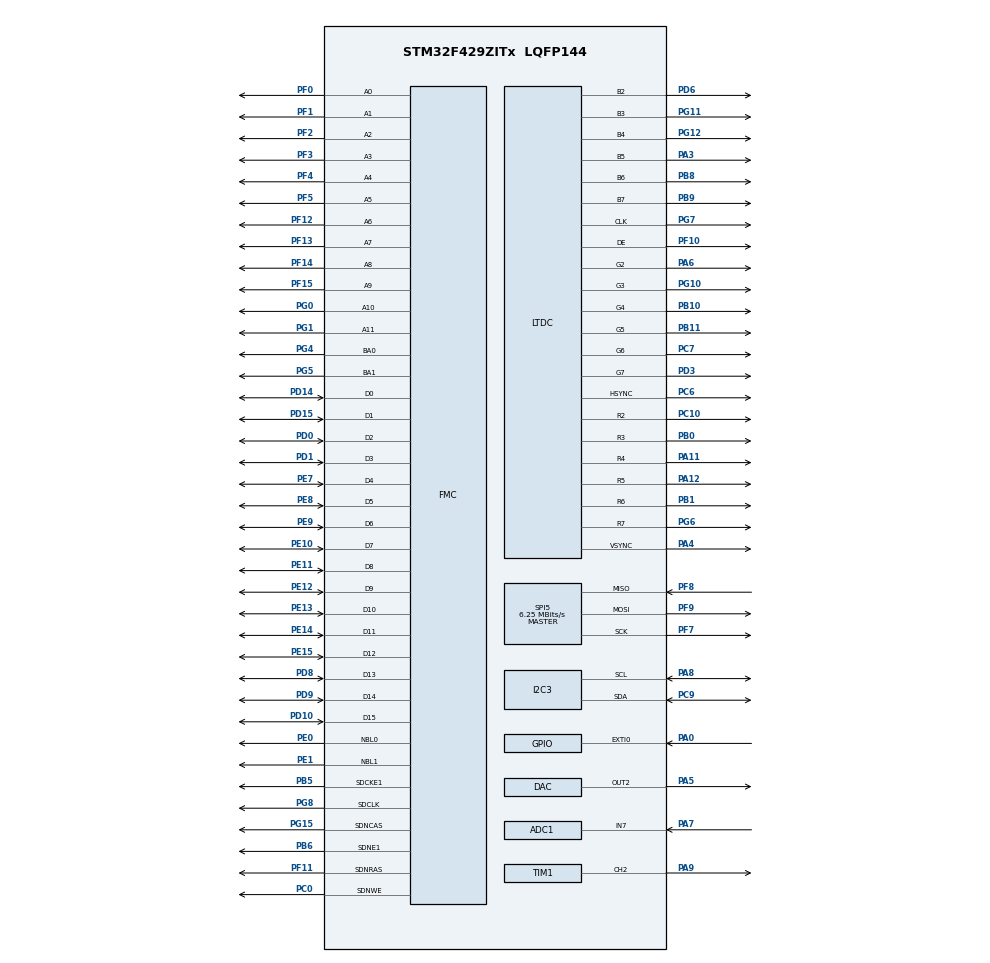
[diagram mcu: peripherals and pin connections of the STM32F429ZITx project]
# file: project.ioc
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ADC1.Channel-0\#ChannelRegularConversion=ADC_CHANNEL_7
ADC1.NbrOfConversionFlag=1
ADC1.Rank-0\#ChannelRegularConversion=1
ADC1.SamplingTime-0\#ChannelRegularConversion=ADC_SAMPLETIME_3CYCLES
ADC1.master=1
DMA2D.ColorMode=DMA2D_OUTPUT_ARGB8888
LTDC.ActiveH=320
LTDC.ActiveW=240
Mcu.Family=STM32F4
Mcu.Name=STM32F429ZITx
Mcu.Package=LQFP144
NVIC.EXTI0_IRQn=true\:0\:0\:false\:false\:true\:true\:true\:true
NVIC.LTDC_IRQn=true\:0\:0\:false\:false\:true\:true\:true\:true
NVIC.PriorityGroup=NVIC_PRIORITYGROUP_4
PA0/WKUP.Signal=GPXTI0
PA11.Mode=RGB666
PA11.Signal=LTDC_R4
PA12.Mode=RGB666
PA12.Signal=LTDC_R5
PA3.Mode=RGB666
PA3.Signal=LTDC_B5
PA4.Mode=RGB666
PA4.Signal=LTDC_VSYNC
PA5.Signal=COMP_DAC2_group
PA6.Mode=RGB666
PA6.Signal=LTDC_G2
PA7.Signal=ADCx_IN7
PA8.Mode=I2C
PA8.Signal=I2C3_SCL
PA9.Signal=S_TIM1_CH2
PB0.Mode=RGB666
PB0.Signal=LTDC_R3
PB1.Mode=RGB666
PB1.Signal=LTDC_R6
PB10.Mode=RGB666
PB10.Signal=LTDC_G4
PB11.Mode=RGB666
PB11.Signal=LTDC_G5
PB5.Mode=SdramChipSelect2_1
PB5.Signal=FMC_SDCKE1
PB6.Mode=SdramChipSelect2_1
PB6.Signal=FMC_SDNE1
PB8.Mode=RGB666
PB8.Signal=LTDC_B6
PB9.Mode=RGB666
PB9.Signal=LTDC_B7
PC0.Signal=FMC_SDNWE
PC10.Mode=RGB666
PC10.Signal=LTDC_R2
PC6.Mode=RGB666
PC6.Signal=LTDC_HSYNC
PC7.Mode=RGB666
PC7.Signal=LTDC_G6
PC9.Mode=I2C
PC9.Signal=I2C3_SDA
PD0.Signal=FMC_D2_DA2
PD1.Signal=FMC_D3_DA3
PD10.Signal=FMC_D15_DA15
PD14.Signal=FMC_D0_DA0
PD15.Signal=FMC_D1_DA1
PD3.Mode=RGB666
PD3.Signal=LTDC_G7
PD6.Mode=RGB666
PD6.Signal=LTDC_B2
PD8.Signal=FMC_D13_DA13
PD9.Signal=FMC_D14_DA14
PE0.Signal=FMC_NBL0
PE1.Signal=FMC_NBL1
PE10.Signal=FMC_D7_DA7
PE11.Signal=FMC_D8_DA8
PE12.Signal=FMC_D9_DA9
PE13.Signal=FMC_D10_DA10
PE14.Signal=FMC_D11_DA11
PE15.Signal=FMC_D12_DA12
PE7.Signal=FMC_D4_DA4
PE8.Signal=FMC_D5_DA5
PE9.Signal=FMC_D6_DA6
PF0.Signal=FMC_A0
PF1.Signal=FMC_A1
PF10.Mode=RGB666
PF10.Signal=LTDC_DE
PF11.Signal=FMC_SDNRAS
PF12.Signal=FMC_A6
PF13.Signal=FMC_A7
PF14.Signal=FMC_A8
PF15.Signal=FMC_A9
PF2.Signal=FMC_A2
PF3.Signal=FMC_A3
PF4.Signal=FMC_A4
PF5.Signal=FMC_A5
PF7.Mode=Full_Duplex_Master
PF7.Signal=SPI5_SCK
PF8.Mode=Full_Duplex_Master
PF8.Signal=SPI5_MISO
PF9.Mode=Full_Duplex_Master
PF9.Signal=SPI5_MOSI
PG0.Signal=FMC_A10
PG1.Signal=FMC_A11
PG10.Mode=RGB666
PG10.Signal=LTDC_G3
PG11.Mode=RGB666
PG11.Signal=LTDC_B3
PG12.Mode=RGB666
PG12.Signal=LTDC_B4
PG15.Signal=FMC_SDNCAS
PG4.Signal=FMC_A14_BA0
PG5.Signal=FMC_A15_BA1
PG6.Mode=RGB666
PG6.Signal=LTDC_R7
PG7.Mode=RGB666
PG7.Signal=LTDC_CLK
PG8.Signal=FMC_SDCLK
PH0/OSC_IN.Mode=HSE-External-Oscillator
PH0/OSC_IN.Signal=RCC_OSC_IN
PH1/OSC_OUT.Mode=HSE-External-Oscillator
PH1/OSC_OUT.Signal=RCC_OSC_OUT
ProjectManager.HeapSize=0x200
ProjectManager.StackSize=0x400
ProjectManager.TargetToolchain=STM32CubeIDE
RCC.48MHZClocksFreq_Value=10000000
RCC.AHBFreq_Value=25000000
RCC.APB1CLKDivider=RCC_HCLK_DIV4
RCC.APB1Freq_Value=6250000
RCC.APB1TimFreq_Value=12500000
RCC.APB2CLKDivider=RCC_HCLK_DIV2
RCC.APB2Freq_Value=12500000
RCC.APB2TimFreq_Value=25000000
RCC.CortexFreq_Value=25000000
RCC.HCLKFreq_Value=25000000
RCC.HSE_VALUE=8000000
RCC.HSI_VALUE=16000000
RCC.LSE_VALUE=32768
RCC.PLLN=100
RCC.PLLQ=5
RCC.PLLSAIR=2
RCC.PLLSourceVirtual=RCC_PLLSOURCE_HSE
RCC.SYSCLKFreq_VALUE=25000000
RCC.SYSCLKSource=RCC_SYSCLKSOURCE_PLLCLK
RCC.VCOOutputFreq_Value=50000000
RTC.Hours=10
RTC.Minutes=15
SH.ADCx_IN7.0=ADC1_IN7,IN7
SH.COMP_DAC2_group.0=DAC_OUT2,DAC_OUT2
SH.FMC_A0.0=FMC_A0,12b-sda1
SH.FMC_A1.0=FMC_A1,12b-sda1
SH.FMC_A10.0=FMC_A10,12b-sda1
SH.FMC_A11.0=FMC_A11,12b-sda1
SH.FMC_A14_BA0.0=FMC_BA0,FourSdramBanks1
SH.FMC_A15_BA1.0=FMC_BA1,FourSdramBanks1
SH.FMC_A2.0=FMC_A2,12b-sda1
SH.FMC_A3.0=FMC_A3,12b-sda1
SH.FMC_A4.0=FMC_A4,12b-sda1
SH.FMC_A5.0=FMC_A5,12b-sda1
SH.FMC_A6.0=FMC_A6,12b-sda1
SH.FMC_A7.0=FMC_A7,12b-sda1
SH.FMC_A8.0=FMC_A8,12b-sda1
SH.FMC_A9.0=FMC_A9,12b-sda1
SH.FMC_D0_DA0.0=FMC_D0,sd-16b-d1
SH.FMC_D10_DA10.0=FMC_D10,sd-16b-d1
SH.FMC_D11_DA11.0=FMC_D11,sd-16b-d1
SH.FMC_D12_DA12.0=FMC_D12,sd-16b-d1
SH.FMC_D13_DA13.0=FMC_D13,sd-16b-d1
SH.FMC_D14_DA14.0=FMC_D14,sd-16b-d1
SH.FMC_D15_DA15.0=FMC_D15,sd-16b-d1
SH.FMC_D1_DA1.0=FMC_D1,sd-16b-d1
SH.FMC_D2_DA2.0=FMC_D2,sd-16b-d1
SH.FMC_D3_DA3.0=FMC_D3,sd-16b-d1
SH.FMC_D4_DA4.0=FMC_D4,sd-16b-d1
SH.FMC_D5_DA5.0=FMC_D5,sd-16b-d1
SH.FMC_D6_DA6.0=FMC_D6,sd-16b-d1
SH.FMC_D7_DA7.0=FMC_D7,sd-16b-d1
SH.FMC_D8_DA8.0=FMC_D8,sd-16b-d1
SH.FMC_D9_DA9.0=FMC_D9,sd-16b-d1
SH.FMC_NBL0.0=FMC_NBL0,Sd2ByteEnable1
SH.FMC_NBL1.0=FMC_NBL1,Sd2ByteEnable1
SH.FMC_SDCLK.0=FMC_SDCLK,12b-sda1
SH.FMC_SDNCAS.0=FMC_SDNCAS,12b-sda1
SH.FMC_SDNRAS.0=FMC_SDNRAS,12b-sda1
SH.FMC_SDNWE.0=FMC_SDNWE,12b-sda1
SH.S_TIM1_CH2.0=TIM1_CH2,PWM Generation2 CH2
SPI5.BaudRatePrescaler=SPI_BAUDRATEPRESCALER_2
SPI5.CalculateBaudRate=6.25 MBits/s
SPI5.Direction=SPI_DIRECTION_2LINES
SPI5.Mode=SPI_MODE_MASTER
SPI5.VirtualType=VM_MASTER
TIM1.Channel-PWM\ Generation2\ CH2=TIM_CHANNEL_2
VP_CRC_VS_CRC.Mode=CRC_Activate
VP_DMA2D_VS_DMA2D.Mode=DMA2D_Activate
VP_RNG_VS_RNG.Mode=RNG_Activate
VP_RTC_VS_RTC_Activate.Mode=RTC_Enabled
VP_RTC_VS_RTC_Calendar.Mode=RTC_Calendar
board=custom

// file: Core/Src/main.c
/* USER CODE BEGIN Header */
/**
 ******************************************************************************
 * @file           : main.c
 * @brief          : Main program body
 ******************************************************************************
 * @attention
 *
 * Copyright (c) 2025 STMicroelectronics.
 * All rights reserved.
 *
 * This software is licensed under terms that can be found in the LICENSE file
 * in the root directory of this software component.
 * If no LICENSE file comes with this software, it is provided AS-IS.
 *
 ******************************************************************************
 */
/* USER CODE END Header */
#include "main.h"

/* USER CODE BEGIN Includes */
#include "stm32f429i_discovery.h"
#include "stm32f429i_discovery_lcd.h"
#include "stm32f429i_discovery_sdram.h"

#include <stdio.h>
#include <stdlib.h>

#include "adc_drv.h"
#include "crc_drv.h"
#include "pwm_drv.h"
#include "rng_utils.h"
#include "rtc_drv.h"
#include "dice.h"
#include "animation.h"
#include "audio.h"
#include "melody.h"
#include "score.h"

/* USER CODE END Includes */

ADC_HandleTypeDef hadc1;

CRC_HandleTypeDef hcrc;

DAC_HandleTypeDef hdac;

DMA2D_HandleTypeDef hdma2d;

I2C_HandleTypeDef hi2c3;

LTDC_HandleTypeDef hltdc;

RNG_HandleTypeDef hrng;

RTC_HandleTypeDef hrtc;

SPI_HandleTypeDef hspi5;

TIM_HandleTypeDef htim1;

SDRAM_HandleTypeDef hsdram1;

/* USER CODE BEGIN PV */
#define ADC_THRESHOLD 5
#define SELECTION_TIMEOUT 5000

extern AudioState_t _audioState;
extern ProtectedScore_t g_HighScoreProtected;
volatile uint8_t g_StartRoll = 0;

typedef enum {
	GAME_START, FIRST_ROLL, SELECTING, REROLL, SCORING
} GameState_t;
GameState_t state = GAME_START;
/* USER CODE END PV */

void SystemClock_Config(void);
static void MX_GPIO_Init(void);
static void MX_RNG_Init(void);
static void MX_DMA2D_Init(void);
static void MX_FMC_Init(void);
static void MX_I2C3_Init(void);
static void MX_LTDC_Init(void);
static void MX_SPI5_Init(void);
static void MX_ADC1_Init(void);
static void MX_CRC_Init(void);
static void MX_DAC_Init(void);
static void MX_RTC_Init(void);
static void MX_TIM1_Init(void);

int main(void) {

	/* MCU Configuration--------------------------------------------------------*/

	/* Reset of all peripherals, Initializes the Flash interface and the Systick. */
	HAL_Init();

	/* Configure the system clock */
	SystemClock_Config();

	/* Initialize all configured peripherals */
	MX_GPIO_Init();
	MX_RNG_Init();
	MX_DMA2D_Init();
	MX_FMC_Init();
	MX_I2C3_Init();
	MX_LTDC_Init();
	MX_SPI5_Init();
	MX_ADC1_Init();
	MX_CRC_Init();
	MX_DAC_Init();
	MX_RTC_Init();
	MX_TIM1_Init();
	/* USER CODE BEGIN 2 */
	// Time initialization
	RTC_SetTime(0, 0, 0);
	RTC_SetDate(0, 0, 0, 0);

	//Video and Audio initialization
	Video_Init();
	Audio_Init(&htim1, TIM_CHANNEL_2);

	// Dice initialization
	const uint16_t count = 5;
	const uint16_t diceSize = 60;

	Dice_t *diceArray[count];
	uint16_t originsX[count];
	uint16_t originsY[count];

	static Dice_t diceObjects[5];
	for (int i = 0; i < count; i++) {
		diceArray[i] = &diceObjects[i];

		if (i == 0 || i == 1) {
			originsY[i] = 70;
			originsX[i] = (i == 0) ? 40 : 140;
		} else if (i == 2) {
			originsY[i] = 135;
			originsX[i] = (240 - diceSize) / 2;
		} else {
			originsY[i] = 200;
			originsX[i] = (i == 3) ? 40 : 140;
		}

		Dice_Init(diceArray[i], originsX[i], originsY[i], diceSize,
		LCD_COLOR_WHITE, LCD_COLOR_RED);
		Dice_SetValue(diceArray[i], RNG_GetValue(1, 6));
	}

	DiceContext_t diceCtx;
	diceCtx.dices = diceArray;
	diceCtx.count = count;
	diceCtx.origX = originsX;
	diceCtx.origY = originsY;

	// Score initialization
	ScoreResult_t res = Dice_CalculateScore(&diceCtx);
	Score_LoadFromBackup();
	if (!IsHighScoreValid()) {
		UpdateHighScore(0, 0);
		Score_SaveToBackup();
	}

	uint32_t highScore = 0;
	uint32_t maxTurns = g_HighScoreProtected.maxTurns;
	uint32_t currentTurns = 0;
	uint32_t currentScore = 0;

	// UI buffors
	char timeBuffer[20];
	char highBuffer[32];
	char turnsBuffer[32];
	char currentBuffer[32];
	char combinationBuffer[32];

	//Reroll mechanism
	uint8_t selectedDiceIndex = 0;
	uint8_t lastPotPercent = 0;
	uint32_t lastActivityTick = 0;
	uint8_t isSelectionActive = 0;

	//Audio test
	//Audio_PlayTone(NOTE_D4, 10);
	uint32_t lastRTCUpdate = 0;

	/* USER CODE END 2 */

	/* Infinite loop */
	/* USER CODE BEGIN WHILE */
	state = GAME_START;
	int8_t lives = 3;
	uint8_t scoringProcessed = 0;

	uint32_t btnPressStart = 0;
	uint8_t btnState = 0;
	const uint32_t LONG_PRESS_MS = 800;

	while (1) {
		/* USER CODE END WHILE */

		/* USER CODE BEGIN 3 */
		uint32_t currentTick = HAL_GetTick();
		uint8_t currentPotPercent = ADC_GetPercentage();
		uint8_t needsRedraw = 0;

		sprintf(highBuffer, "BEST: %lu", highScore);
		sprintf(currentBuffer, "SCORE: %lu", currentScore);
		sprintf(combinationBuffer, "COMBO: %s", res.name);
		sprintf(turnsBuffer, "%lu/%lu", currentTurns, maxTurns);
		RTC_GetTimeStr(timeBuffer);

		if (state
				== SELECTING&& abs((int) currentPotPercent - (int) lastPotPercent) > ADC_THRESHOLD) {
			isSelectionActive = 1;
			lastActivityTick = currentTick;
			lastPotPercent = currentPotPercent;

			selectedDiceIndex =
					(currentPotPercent >= 100) ? 4 : (currentPotPercent / 20);

			needsRedraw = 1;
		}

		if (currentTick - lastRTCUpdate >= 1000) {
			RTC_GetTimeStr(timeBuffer);
			lastRTCUpdate = currentTick;
			needsRedraw = 1;
		}

		if (isSelectionActive
				&& (currentTick - lastActivityTick > SELECTION_TIMEOUT)) {
			isSelectionActive = 0;
			needsRedraw = 1;
		}

		if (_audioState == AUDIO_IDLE && g_StartRoll == 0) {
			Audio_Play(startMelody, sizeof(startMelody) / sizeof(uint32_t));
		}

		switch (state) {
		case GAME_START:
			if (g_StartRoll) {
				g_StartRoll = 0;
				lives = 3;

				state = FIRST_ROLL;
				needsRedraw = 1;
			}
			break;

		case FIRST_ROLL:
			for (int i = 0; i < 5; i++)
				diceArray[i]->isLocked = 0;

			Audio_Play(rollMelody, sizeof(rollMelody) / sizeof(uint32_t));
			Anim_Run(15, &diceCtx, Dice_UpdateLogic, Dice_DrawLogic);
			Dice_RestoreOrigin(&diceCtx);

			res = Dice_CalculateScore(&diceCtx);
			currentScore = res.points;

			lastActivityTick = HAL_GetTick();
			state = SELECTING;
			needsRedraw = 1;
			break;

		case SELECTING:
			int newIndex =
					(currentPotPercent >= 100) ? 4 : (currentPotPercent / 20);
			if (newIndex != selectedDiceIndex) {
				selectedDiceIndex = newIndex;
				lastActivityTick = currentTick;
				needsRedraw = 1;
			}

			g_StartRoll = 0;

			if (HAL_GPIO_ReadPin(GPIOA, GPIO_PIN_0) == GPIO_PIN_SET) {
				if (btnState == 0) {
					btnState = 1;
					btnPressStart = currentTick;
				} else if (btnState == 1) {
					if ((currentTick - btnPressStart) > LONG_PRESS_MS) {
						state = REROLL;
						btnState = 2;
					}
				}
			} else {
				if (btnState == 1) {
					diceArray[selectedDiceIndex]->isLocked =
							!diceArray[selectedDiceIndex]->isLocked;
					needsRedraw = 1;
				}
				btnState = 0;
			}

			break;

		case REROLL:
			Dice_t *rerollArray[5];
			uint16_t rerollOrigX[5];
			uint16_t rerollOrigY[5];
			uint8_t rerollCount = 0;

			for (int i = 0; i < 5; i++) {
				if (!diceArray[i]->isLocked) {
					rerollArray[rerollCount] = diceArray[i];
					rerollOrigX[rerollCount] = originsX[i];
					rerollOrigY[rerollCount] = originsY[i];
					rerollCount++;
				}
			}

			if (rerollCount > 0) {
				DiceContext_t rerollCtx =
						{ .dices = rerollArray, .count = rerollCount, .origX =
								rerollOrigX, .origY = rerollOrigY };

				Audio_Play(rollMelody, sizeof(rollMelody) / sizeof(uint32_t));
				Anim_Run(20, &rerollCtx, Dice_UpdateLogic, Dice_DrawLogic);
				Dice_RestoreOrigin(&rerollCtx);
			}
			state = SCORING;
			scoringProcessed = 0;
			needsRedraw = 1;
			break;

		case SCORING:
			if (!scoringProcessed) {
				res = Dice_CalculateScore(&diceCtx);
				needsRedraw = 1;
				scoringProcessed = 1;

				currentTurns++;
				if (currentTurns > maxTurns) {
					maxTurns = currentTurns;
				}

				if (currentScore > highScore) {
					highScore = currentScore;
					UpdateHighScore(highScore, maxTurns);
					Score_SaveToBackup();

					Audio_Play(winMelody, sizeof(winMelody) / sizeof(uint32_t));
				} else {
					lives--;
					if (lives <= 0) {
						Audio_Play(gameOverMelody,
								sizeof(gameOverMelody) / sizeof(uint32_t));

						highScore = 0;
						currentTurns = 0;
						UpdateHighScore(0, maxTurns);
						Score_SaveToBackup();
					} else {
						Audio_Play(loseLifeMelody,
								sizeof(loseLifeMelody) / sizeof(uint32_t));
					}
					needsRedraw = 1;
				}

				for (int i = 0; i < 5; i++)
					diceArray[i]->isLocked = 0;
			}

			if (g_StartRoll) {
				g_StartRoll = 0;

				if (lives <= 0 || currentScore > highScore) {
					lives = 3;
					state = GAME_START;
				} else {
					state = FIRST_ROLL;
				}
				needsRedraw = 1;
			}

			break;
		}

		if (needsRedraw) {
			BSP_LCD_Clear(LCD_COLOR_BLACK);
			Dice_DrawLogic(&diceCtx);

			if (isSelectionActive) {
				Dice_t *sel = diceArray[selectedDiceIndex];
				BSP_LCD_SetTextColor(LCD_COLOR_BLUE);
				BSP_LCD_DrawRect(sel->x - 2, sel->y - 2, sel->size + 4,
						sel->size + 4);
			}

			DrawLifeIndicator(10, 10, lives);

			BSP_LCD_SetFont(&Font16);
			BSP_LCD_SetBackColor(LCD_COLOR_DARKMAGENTA);
			BSP_LCD_SetTextColor(LCD_COLOR_YELLOW);
			BSP_LCD_DisplayStringAt(0, 10, (uint8_t*) turnsBuffer, RIGHT_MODE);
			BSP_LCD_SetBackColor(LCD_COLOR_WHITE);

			BSP_LCD_SetFont(&Font20);
			BSP_LCD_SetTextColor(LCD_COLOR_BLUE);
			BSP_LCD_DisplayStringAt(0, 10, (uint8_t*) highBuffer, CENTER_MODE);
			BSP_LCD_DisplayStringAt(0, 35, (uint8_t*) currentBuffer,
					CENTER_MODE);
			BSP_LCD_DisplayStringAt(0, 290, (uint8_t*) timeBuffer, CENTER_MODE);

			if (state == SCORING) {
				BSP_LCD_SetFont(&Font16);
				BSP_LCD_SetTextColor(LCD_COLOR_RED);
				BSP_LCD_DisplayStringAt(0, 270, (uint8_t*) combinationBuffer,
						CENTER_MODE);
			}

			SwapBuffers();
		}
	}
	/* USER CODE END 3 */
}

void SystemClock_Config(void) {
	RCC_OscInitTypeDef RCC_OscInitStruct = { 0 };
	RCC_ClkInitTypeDef RCC_ClkInitStruct = { 0 };

	/** Configure the main internal regulator output voltage
	 */
	__HAL_RCC_PWR_CLK_ENABLE();
	__HAL_PWR_VOLTAGESCALING_CONFIG(PWR_REGULATOR_VOLTAGE_SCALE3);

	/** Initializes the RCC Oscillators according to the specified parameters
	 * in the RCC_OscInitTypeDef structure.
	 */
	RCC_OscInitStruct.OscillatorType = RCC_OSCILLATORTYPE_LSI
			| RCC_OSCILLATORTYPE_HSE;
	RCC_OscInitStruct.HSEState = RCC_HSE_ON;
	RCC_OscInitStruct.LSIState = RCC_LSI_ON;
	RCC_OscInitStruct.PLL.PLLState = RCC_PLL_ON;
	RCC_OscInitStruct.PLL.PLLSource = RCC_PLLSOURCE_HSE;
	RCC_OscInitStruct.PLL.PLLM = 16;
	RCC_OscInitStruct.PLL.PLLN = 180;
	RCC_OscInitStruct.PLL.PLLP = RCC_PLLP_DIV2;
	RCC_OscInitStruct.PLL.PLLQ = 4;
	if (HAL_RCC_OscConfig(&RCC_OscInitStruct) != HAL_OK) {
		Error_Handler();
	}

	/** Initializes the CPU, AHB and APB buses clocks
	 */
	RCC_ClkInitStruct.ClockType = RCC_CLOCKTYPE_HCLK | RCC_CLOCKTYPE_SYSCLK
			| RCC_CLOCKTYPE_PCLK1 | RCC_CLOCKTYPE_PCLK2;
	RCC_ClkInitStruct.SYSCLKSource = RCC_SYSCLKSOURCE_PLLCLK;
	RCC_ClkInitStruct.AHBCLKDivider = RCC_SYSCLK_DIV1;
	RCC_ClkInitStruct.APB1CLKDivider = RCC_HCLK_DIV4;
	RCC_ClkInitStruct.APB2CLKDivider = RCC_HCLK_DIV2;

	if (HAL_RCC_ClockConfig(&RCC_ClkInitStruct, FLASH_LATENCY_1) != HAL_OK) {
		Error_Handler();
	}
}

static void MX_ADC1_Init(void) {

	ADC_ChannelConfTypeDef sConfig = { 0 };

	/** Configure the global features of the ADC (Clock, Resolution, Data Alignment and number of conversion)
	 */
	hadc1.Instance = ADC1;
	hadc1.Init.ClockPrescaler = ADC_CLOCK_SYNC_PCLK_DIV2;
	hadc1.Init.Resolution = ADC_RESOLUTION_12B;
	hadc1.Init.ScanConvMode = DISABLE;
	hadc1.Init.ContinuousConvMode = DISABLE;
	hadc1.Init.DiscontinuousConvMode = DISABLE;
	hadc1.Init.ExternalTrigConvEdge = ADC_EXTERNALTRIGCONVEDGE_NONE;
	hadc1.Init.ExternalTrigConv = ADC_SOFTWARE_START;
	hadc1.Init.DataAlign = ADC_DATAALIGN_RIGHT;
	hadc1.Init.NbrOfConversion = 1;
	hadc1.Init.DMAContinuousRequests = DISABLE;
	hadc1.Init.EOCSelection = ADC_EOC_SINGLE_CONV;
	if (HAL_ADC_Init(&hadc1) != HAL_OK) {
		Error_Handler();
	}

	/** Configure for the selected ADC regular channel its corresponding rank in the sequencer and its sample time.
	 */
	sConfig.Channel = ADC_CHANNEL_7;
	sConfig.Rank = 1;
	sConfig.SamplingTime = ADC_SAMPLETIME_3CYCLES;
	if (HAL_ADC_ConfigChannel(&hadc1, &sConfig) != HAL_OK) {
		Error_Handler();
	}

}

static void MX_CRC_Init(void) {

	hcrc.Instance = CRC;
	if (HAL_CRC_Init(&hcrc) != HAL_OK) {
		Error_Handler();
	}

}

static void MX_DAC_Init(void) {

	DAC_ChannelConfTypeDef sConfig = { 0 };

	/** DAC Initialization
	 */
	hdac.Instance = DAC;
	if (HAL_DAC_Init(&hdac) != HAL_OK) {
		Error_Handler();
	}

	/** DAC channel OUT2 config
	 */
	sConfig.DAC_Trigger = DAC_TRIGGER_NONE;
	sConfig.DAC_OutputBuffer = DAC_OUTPUTBUFFER_ENABLE;
	if (HAL_DAC_ConfigChannel(&hdac, &sConfig, DAC_CHANNEL_2) != HAL_OK) {
		Error_Handler();
	}

}

static void MX_DMA2D_Init(void) {

	hdma2d.Instance = DMA2D;
	hdma2d.Init.Mode = DMA2D_M2M;
	hdma2d.Init.ColorMode = DMA2D_OUTPUT_ARGB8888;
	hdma2d.Init.OutputOffset = 0;
	hdma2d.LayerCfg[1].InputOffset = 0;
	hdma2d.LayerCfg[1].InputColorMode = DMA2D_INPUT_ARGB8888;
	hdma2d.LayerCfg[1].AlphaMode = DMA2D_NO_MODIF_ALPHA;
	hdma2d.LayerCfg[1].InputAlpha = 0;
	if (HAL_DMA2D_Init(&hdma2d) != HAL_OK) {
		Error_Handler();
	}
	if (HAL_DMA2D_ConfigLayer(&hdma2d, 1) != HAL_OK) {
		Error_Handler();
	}

}

static void MX_I2C3_Init(void) {

	hi2c3.Instance = I2C3;
	hi2c3.Init.ClockSpeed = 100000;
	hi2c3.Init.DutyCycle = I2C_DUTYCYCLE_2;
	hi2c3.Init.OwnAddress1 = 0;
	hi2c3.Init.AddressingMode = I2C_ADDRESSINGMODE_7BIT;
	hi2c3.Init.DualAddressMode = I2C_DUALADDRESS_DISABLE;
	hi2c3.Init.OwnAddress2 = 0;
	hi2c3.Init.GeneralCallMode = I2C_GENERALCALL_DISABLE;
	hi2c3.Init.NoStretchMode = I2C_NOSTRETCH_DISABLE;
	if (HAL_I2C_Init(&hi2c3) != HAL_OK) {
		Error_Handler();
	}

	/** Configure Analogue filter
	 */
	if (HAL_I2CEx_ConfigAnalogFilter(&hi2c3, I2C_ANALOGFILTER_ENABLE)
			!= HAL_OK) {
		Error_Handler();
	}

	/** Configure Digital filter
	 */
	if (HAL_I2CEx_ConfigDigitalFilter(&hi2c3, 0) != HAL_OK) {
		Error_Handler();
	}

}

static void MX_LTDC_Init(void) {

	LTDC_LayerCfgTypeDef pLayerCfg = { 0 };
	LTDC_LayerCfgTypeDef pLayerCfg1 = { 0 };

	hltdc.Instance = LTDC;
	hltdc.Init.HSPolarity = LTDC_HSPOLARITY_AL;
	hltdc.Init.VSPolarity = LTDC_VSPOLARITY_AL;
	hltdc.Init.DEPolarity = LTDC_DEPOLARITY_AL;
	hltdc.Init.PCPolarity = LTDC_PCPOLARITY_IPC;
	hltdc.Init.HorizontalSync = 7;
	hltdc.Init.VerticalSync = 3;
	hltdc.Init.AccumulatedHBP = 14;
	hltdc.Init.AccumulatedVBP = 5;
	hltdc.Init.AccumulatedActiveW = 254;
	hltdc.Init.AccumulatedActiveH = 325;
	hltdc.Init.TotalWidth = 260;
	hltdc.Init.TotalHeigh = 327;
	hltdc.Init.Backcolor.Blue = 0;
	hltdc.Init.Backcolor.Green = 0;
	hltdc.Init.Backcolor.Red = 0;
	if (HAL_LTDC_Init(&hltdc) != HAL_OK) {
		Error_Handler();
	}
	pLayerCfg.WindowX0 = 0;
	pLayerCfg.WindowX1 = 240;
	pLayerCfg.WindowY0 = 0;
	pLayerCfg.WindowY1 = 320;
	pLayerCfg.PixelFormat = LTDC_PIXEL_FORMAT_ARGB8888;
	pLayerCfg.Alpha = 255;
	pLayerCfg.Alpha0 = 0;
	pLayerCfg.BlendingFactor1 = LTDC_BLENDING_FACTOR1_CA;
	pLayerCfg.BlendingFactor2 = LTDC_BLENDING_FACTOR2_CA;
	pLayerCfg.FBStartAdress = LCD_FRAME_BUFFER;
	pLayerCfg.ImageWidth = 240;
	pLayerCfg.ImageHeight = 320;
	pLayerCfg.Backcolor.Blue = 0;
	pLayerCfg.Backcolor.Green = 0;
	pLayerCfg.Backcolor.Red = 0;
	if (HAL_LTDC_ConfigLayer(&hltdc, &pLayerCfg, 0) != HAL_OK) {
		Error_Handler();
	}
	pLayerCfg1.WindowX0 = 0;
	pLayerCfg1.WindowX1 = 240;
	pLayerCfg1.WindowY0 = 0;
	pLayerCfg1.WindowY1 = 320;
	pLayerCfg1.PixelFormat = LTDC_PIXEL_FORMAT_ARGB8888;
	pLayerCfg1.Alpha = 255;
	pLayerCfg1.Alpha0 = 0;
	pLayerCfg1.BlendingFactor1 = LTDC_BLENDING_FACTOR1_CA;
	pLayerCfg1.BlendingFactor2 = LTDC_BLENDING_FACTOR2_CA;
	pLayerCfg1.FBStartAdress = LCD_FRAME_BUFFER + (240 * 320 * 4);
	pLayerCfg1.ImageWidth = 240;
	pLayerCfg1.ImageHeight = 320;
	pLayerCfg1.Backcolor.Blue = 0;
	pLayerCfg1.Backcolor.Green = 0;
	pLayerCfg1.Backcolor.Red = 0;
	if (HAL_LTDC_ConfigLayer(&hltdc, &pLayerCfg1, 1) != HAL_OK) {
		Error_Handler();
	}

}

static void MX_RNG_Init(void) {

	hrng.Instance = RNG;
	if (HAL_RNG_Init(&hrng) != HAL_OK) {
		Error_Handler();
	}

}

static void MX_RTC_Init(void) {

	RTC_TimeTypeDef sTime = { 0 };
	RTC_DateTypeDef sDate = { 0 };

	/** Initialize RTC Only
	 */
	hrtc.Instance = RTC;
	hrtc.Init.HourFormat = RTC_HOURFORMAT_24;
	hrtc.Init.AsynchPrediv = 127;
	hrtc.Init.SynchPrediv = 255;
	hrtc.Init.OutPut = RTC_OUTPUT_DISABLE;
	hrtc.Init.OutPutPolarity = RTC_OUTPUT_POLARITY_HIGH;
	hrtc.Init.OutPutType = RTC_OUTPUT_TYPE_OPENDRAIN;
	if (HAL_RTC_Init(&hrtc) != HAL_OK) {
		Error_Handler();
	}

	/** Initialize RTC and set the Time and Date
	 */
	sTime.Hours = 0x10;
	sTime.Minutes = 0x15;
	sTime.Seconds = 0x0;
	sTime.DayLightSaving = RTC_DAYLIGHTSAVING_NONE;
	sTime.StoreOperation = RTC_STOREOPERATION_RESET;
	if (HAL_RTC_SetTime(&hrtc, &sTime, RTC_FORMAT_BCD) != HAL_OK) {
		Error_Handler();
	}
	sDate.WeekDay = RTC_WEEKDAY_MONDAY;
	sDate.Month = RTC_MONTH_JANUARY;
	sDate.Date = 0x1;
	sDate.Year = 0x0;

	if (HAL_RTC_SetDate(&hrtc, &sDate, RTC_FORMAT_BCD) != HAL_OK) {
		Error_Handler();
	}

}

static void MX_SPI5_Init(void) {

	/* SPI5 parameter configuration*/
	hspi5.Instance = SPI5;
	hspi5.Init.Mode = SPI_MODE_MASTER;
	hspi5.Init.Direction = SPI_DIRECTION_2LINES;
	hspi5.Init.DataSize = SPI_DATASIZE_8BIT;
	hspi5.Init.CLKPolarity = SPI_POLARITY_LOW;
	hspi5.Init.CLKPhase = SPI_PHASE_1EDGE;
	hspi5.Init.NSS = SPI_NSS_SOFT;
	hspi5.Init.BaudRatePrescaler = SPI_BAUDRATEPRESCALER_2;
	hspi5.Init.FirstBit = SPI_FIRSTBIT_MSB;
	hspi5.Init.TIMode = SPI_TIMODE_DISABLE;
	hspi5.Init.CRCCalculation = SPI_CRCCALCULATION_DISABLE;
	hspi5.Init.CRCPolynomial = 10;
	if (HAL_SPI_Init(&hspi5) != HAL_OK) {
		Error_Handler();
	}

}

static void MX_TIM1_Init(void) {

	TIM_MasterConfigTypeDef sMasterConfig = { 0 };
	TIM_OC_InitTypeDef sConfigOC = { 0 };
	TIM_BreakDeadTimeConfigTypeDef sBreakDeadTimeConfig = { 0 };

	htim1.Instance = TIM1;
	htim1.Init.Prescaler = 24;
	htim1.Init.CounterMode = TIM_COUNTERMODE_UP;
	htim1.Init.Period = 1000;
	htim1.Init.ClockDivision = TIM_CLOCKDIVISION_DIV1;
	htim1.Init.RepetitionCounter = 0;
	htim1.Init.AutoReloadPreload = TIM_AUTORELOAD_PRELOAD_DISABLE;
	if (HAL_TIM_PWM_Init(&htim1) != HAL_OK) {
		Error_Handler();
	}
	sMasterConfig.MasterOutputTrigger = TIM_TRGO_RESET;
	sMasterConfig.MasterSlaveMode = TIM_MASTERSLAVEMODE_DISABLE;
	if (HAL_TIMEx_MasterConfigSynchronization(&htim1, &sMasterConfig)
			!= HAL_OK) {
		Error_Handler();
	}
	sConfigOC.OCMode = TIM_OCMODE_PWM1;
	sConfigOC.Pulse = 0;
	sConfigOC.OCPolarity = TIM_OCPOLARITY_HIGH;
	sConfigOC.OCNPolarity = TIM_OCNPOLARITY_HIGH;
	sConfigOC.OCFastMode = TIM_OCFAST_DISABLE;
	sConfigOC.OCIdleState = TIM_OCIDLESTATE_RESET;
	sConfigOC.OCNIdleState = TIM_OCNIDLESTATE_RESET;
	if (HAL_TIM_PWM_ConfigChannel(&htim1, &sConfigOC, TIM_CHANNEL_2)
			!= HAL_OK) {
		Error_Handler();
	}
	sBreakDeadTimeConfig.OffStateRunMode = TIM_OSSR_DISABLE;
	sBreakDeadTimeConfig.OffStateIDLEMode = TIM_OSSI_DISABLE;
	sBreakDeadTimeConfig.LockLevel = TIM_LOCKLEVEL_OFF;
	sBreakDeadTimeConfig.DeadTime = 0;
	sBreakDeadTimeConfig.BreakState = TIM_BREAK_DISABLE;
	sBreakDeadTimeConfig.BreakPolarity = TIM_BREAKPOLARITY_HIGH;
	sBreakDeadTimeConfig.AutomaticOutput = TIM_AUTOMATICOUTPUT_DISABLE;
	if (HAL_TIMEx_ConfigBreakDeadTime(&htim1, &sBreakDeadTimeConfig)
			!= HAL_OK) {
		Error_Handler();
	}
	HAL_TIM_MspPostInit(&htim1);

}

/* FMC initialization function */
static void MX_FMC_Init(void) {

	FMC_SDRAM_TimingTypeDef SdramTiming = { 0 };

	/** Perform the SDRAM1 memory initialization sequence
	 */
	hsdram1.Instance = FMC_SDRAM_DEVICE;
	/* hsdram1.Init */
	hsdram1.Init.SDBank = FMC_SDRAM_BANK2;
	hsdram1.Init.ColumnBitsNumber = FMC_SDRAM_COLUMN_BITS_NUM_8;
	hsdram1.Init.RowBitsNumber = FMC_SDRAM_ROW_BITS_NUM_12;
	hsdram1.Init.MemoryDataWidth = FMC_SDRAM_MEM_BUS_WIDTH_16;
	hsdram1.Init.InternalBankNumber = FMC_SDRAM_INTERN_BANKS_NUM_4;
	hsdram1.Init.CASLatency = FMC_SDRAM_CAS_LATENCY_1;
	hsdram1.Init.WriteProtection = FMC_SDRAM_WRITE_PROTECTION_DISABLE;
	hsdram1.Init.SDClockPeriod = FMC_SDRAM_CLOCK_DISABLE;
	hsdram1.Init.ReadBurst = FMC_SDRAM_RBURST_DISABLE;
	hsdram1.Init.ReadPipeDelay = FMC_SDRAM_RPIPE_DELAY_0;
	/* SdramTiming */
	SdramTiming.LoadToActiveDelay = 16;
	SdramTiming.ExitSelfRefreshDelay = 16;
	SdramTiming.SelfRefreshTime = 16;
	SdramTiming.RowCycleDelay = 16;
	SdramTiming.WriteRecoveryTime = 16;
	SdramTiming.RPDelay = 16;
	SdramTiming.RCDDelay = 16;

	if (HAL_SDRAM_Init(&hsdram1, &SdramTiming) != HAL_OK) {
		Error_Handler();
	}

}

static void MX_GPIO_Init(void) {
	GPIO_InitTypeDef GPIO_InitStruct = { 0 };

	/* GPIO Ports Clock Enable */
	__HAL_RCC_GPIOF_CLK_ENABLE();
	__HAL_RCC_GPIOH_CLK_ENABLE();
	__HAL_RCC_GPIOC_CLK_ENABLE();
	__HAL_RCC_GPIOA_CLK_ENABLE();
	__HAL_RCC_GPIOB_CLK_ENABLE();
	__HAL_RCC_GPIOG_CLK_ENABLE();
	__HAL_RCC_GPIOE_CLK_ENABLE();
	__HAL_RCC_GPIOD_CLK_ENABLE();

	/*Configure GPIO pin : PA0 */
	GPIO_InitStruct.Pin = GPIO_PIN_0;
	GPIO_InitStruct.Mode = GPIO_MODE_IT_RISING;
	GPIO_InitStruct.Pull = GPIO_NOPULL;
	HAL_GPIO_Init(GPIOA, &GPIO_InitStruct);

	/* EXTI interrupt init*/
	HAL_NVIC_SetPriority(EXTI0_IRQn, 14, 0);
	HAL_NVIC_EnableIRQ(EXTI0_IRQn);

}

/* USER CODE BEGIN 4 */
void HAL_GPIO_EXTI_Callback(uint16_t GPIO_Pin) {
	if (GPIO_Pin == GPIO_PIN_0 && state != SELECTING) // Sprawdzamy, czy to nasz User Button (PA0)
	{
		static uint32_t last_tick = 0;
		uint32_t current_tick = HAL_GetTick();

		// Prosty debouncing: ignoruj naciśnięcia częstsze niż co 200ms
		if ((current_tick - last_tick) > 200) {
			g_StartRoll = 1; // Ustawiamy flagę - "Hej, pętlo główna, czas na rzut!"
			last_tick = current_tick;
		}
	}
}
/* USER CODE END 4 */

void Error_Handler(void) {
	__disable_irq();
	while (1) {
	}
}
